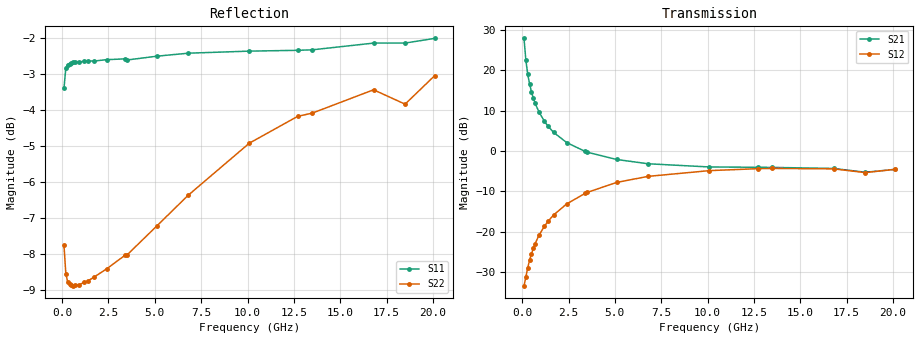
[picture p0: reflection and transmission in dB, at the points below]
!  Infineon Technologies AG
! BFR380L3 , PF131585-7, No.6, Th 09.10.01, soldered on pcb-board, measured with PP GSG850
!  Vce=0.75 V,  Ic=75.0 mA
! Common Emitter S-Parameters:  15. November 2001
#  GHz  S  MA  R  50
! f  S11  S21  S12  S22
! GHz  Mag  Ang  Mag  Ang  Mag  Ang  Mag  Ang
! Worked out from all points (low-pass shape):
!   201 points, 100 MHz to 20.1 GHz, reference 50 ohm
!   highest |S21| = 27.90 dB at 100 MHz (marker M1); lowest = -5.3 dB at 18.5 GHz (marker M2)
!   |S21| within 3 dB of the highest: start of sweep to 154.8 MHz
!   lowest |S11| = -3.4 dB at 100 MHz (marker M3), VSWR 5.20, Z = 10.2 - j12.5 ohm
!   |S11| at or under -10 dB: nowhere
!   |S22| runs from -8.9 to -3.0 dB; largest |S21 - S12| = 25
!   S11 on the Smith chart (normalised r, x): 100 MHz: 0.20, -0.25; 900 MHz: 0.15, +0.09; 3.4 GHz: 0.18, +0.43; 6.8 GHz: 0.25, +0.89; 12.7 GHz: 0.52, +1.63; 20.1 GHz: 1.03, +2.66
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0.1  0.6772 -150.8  24.83 111.9  0.02147 47.8  0.4092 -120.0
0.2  0.7227 -167.2  13.23 98.5  0.02746 54.5  0.3736 -148.3
0.3  0.7299 -173.8  8.949 92.9  0.03583 60.5  0.3641 -159.6
0.4  0.7321 -178.0  6.756 89.0  0.04429 64.1  0.3611 -165.8
0.5  0.7342 178.7  5.425 85.9  0.05312 66.8  0.3604 -169.9
0.6  0.7358 176.2  4.534 83.4  0.0624 68.0  0.3597 -172.9
0.7  0.736 173.9  3.903 81.0  0.0714 68.7  0.3602 -175.2
0.9  0.7361 169.9  3.059 76.7  0.08984 69.1  0.3608 -178.9
1.2  0.738 164.5  2.33 70.9  0.1169 68.4  0.3635 177.1
1.4  0.7385 161.1  2.019 67.3  0.135 67.4  0.3654 174.7
1.7  0.7384 156.3  1.697 62.1  0.1615 65.5  0.3694 171.6
2.4  0.7416 145.8  1.272 51.3  0.221 60.1  0.3796 165.0
3.4  0.7436 131.9  0.9865 38.1  0.2989 51.7  0.3966 156.1
3.5  0.7409 130.6  0.9678 37.0  0.3066 50.8  0.3969 155.5
5.1  0.7499 111.7  0.7848 21.2  0.4083 37.2  0.4353 141.8
6.8  0.7572 94.9  0.6945 9.5  0.4853 24.3  0.4805 127.5
10.1  0.7622 71.6  0.6343 -6.5  0.5712 2.9  0.5677 104.5
12.7  0.7642 59.4  0.6285 -17.7  0.6041 -11.7  0.6185 87.6
13.5  0.7654 56.0  0.6262 -21.1  0.608 -16.0  0.6251 83.3
16.8  0.7821 45.1  0.6081 -32.6  0.6011 -29.8  0.6735 66.8
18.5  0.7821 43.6  0.5454 -40.3  0.5401 -37.5  0.6432 63.1
20.1  0.794 36.7  0.5922 -43.4  0.592 -42.0  0.7048 53.4
